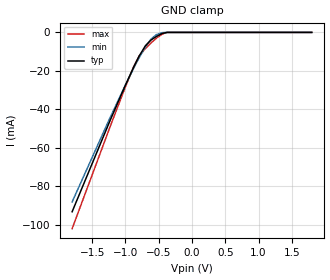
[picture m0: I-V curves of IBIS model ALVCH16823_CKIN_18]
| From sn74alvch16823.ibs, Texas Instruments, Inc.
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[Model]   ALVCH16823_CKIN_18
Model_type  Input
Vinl=0.5775
Vinh=1.2675
| variable   typ   min   max
C_comp   2.88pF   2.16pF   3.34pF
[Temperature Range]   40   100   -40
| Ambient temperature   25   85   -40
[Voltage range]   1.8   1.65   1.95
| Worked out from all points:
|   GND clamp passes 1 mA (typ) near -0.48 V on its own axis
[GND Clamp]
| ALVCH16823_CKIN_18
|   Voltage   I(typ)   I(min)   I(max)
-1.8V     -93.3mA    -88.19mA   -102.1mA
-1.235V   -46.25mA   -44.72mA   -49.56mA
-1V       -27.5mA    -27.4mA    -28.37mA
-875mV    -18.04mA   -18.61mA   -17.75mA
-795mV    -12.45mA   -13.28mA   -12.37mA
-700mV    -6.981mA   -7.539mA   -8.412mA
-615mV    -3.968mA   -3.483mA   -5.497mA
-535mV    -2.13mA    -1.195mA   -3.054mA
-445mV    -515.8uA   -125.4uA   -861.2uA
-375mV    -85.17nA   -8.524uA   -4.38uA
1.8V      24.55pA    142.2pA    23.4pA
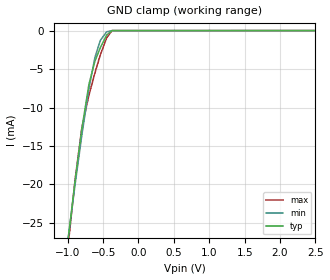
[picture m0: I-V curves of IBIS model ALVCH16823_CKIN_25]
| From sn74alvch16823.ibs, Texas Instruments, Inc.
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[Model]   ALVCH16823_CKIN_25
Model_type  Input
Vinl=0.7
Vinh=1.7
| variable   typ   min   max
C_comp   2.81pF   2.05pF   3.37pF
[Temperature Range]   40   100   -40
| Ambient temperature   25   85   -40
[Voltage range]   2.5   2.3   2.7
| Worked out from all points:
|   GND clamp passes 1 mA (typ) near -0.48 V on its own axis
[GND Clamp]
| ALVCH16823_CKIN_25
|   Voltage   I(typ)   I(min)   I(max)
-2.5V     -153.1mA   -143.6mA   -168.5mA
-1.145V   -38.97mA   -38mA      -41.38mA
-1.11V    -36.17mA   -35.41mA   -38.21mA
-1.08V    -33.78mA   -33.21mA   -35.51mA
-895mV    -19.51mA   -19.99mA   -19.35mA
-800mV    -12.78mA   -13.61mA   -12.64mA
-700mV    -6.981mA   -7.539mA   -8.412mA
-615mV    -3.968mA   -3.483mA   -5.497mA
-540mV    -2.234mA   -1.292mA   -3.196mA
-450mV    -586.7uA   -156.6uA   -959.9uA
-375mV    -85.17nA   -8.524uA   -4.38uA
2.5V      34.28pA    152.6pA    32.5pA
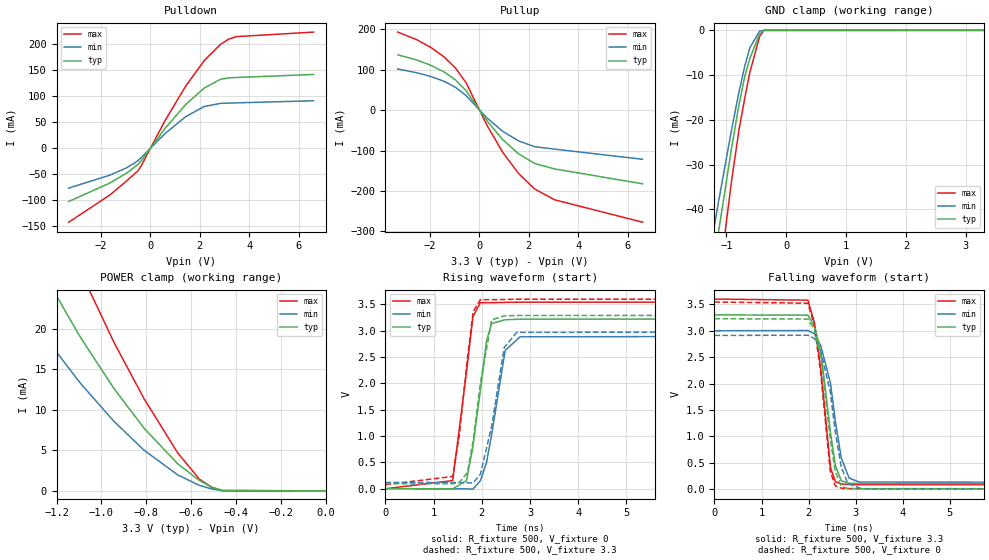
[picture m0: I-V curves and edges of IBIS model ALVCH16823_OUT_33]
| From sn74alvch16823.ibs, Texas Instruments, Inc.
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[Model]   ALVCH16823_OUT_33
Model_type  3-state
Enable   Active-Low
Vref =   0
Rref =   500
Cref =   50p
Vmeas =   1.5
| variable   typ   min   max
C_comp   3.15pF   2.78pF   3.51pF
| C_pullup   4.51pF   3.46pF   5.58pF
| C_pulldown   3.69pF   3.02pF   4.93pF
| C_tri-state   3.15pF   2.78pF   3.51pF
[Temperature Range]   40   100   -40
| Ambient temperature   25   85   -40
[Voltage range]   3.3   3   3.6
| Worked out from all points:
|   slope of the pulldown table from 0 to 0.495 V, typ, clamps not added: 15.7 ohm
|   slope of the pullup table from 0 to 0.495 V, typ, clamps not added: 12 ohm
|   GND clamp passes 1 mA (typ) near -0.45 V on its own axis
|   POWER clamp passes 1 mA (typ) near -0.55 V on its own axis
|   rising waveform, R_fixture 500, V_fixture 0: 20-80 % time 272ps typ, 298ps min, 249ps max; typ from 0 V to 3.23 V
|   falling waveform, R_fixture 500, V_fixture 3.3: 20-80 % time 263ps typ, 302ps min, 236ps max; typ from 3.3 V to 0.098 V
|   rising waveform, R_fixture 500, V_fixture 3.3: 20-80 % time 266ps typ, 295ps min, 249ps max; typ from 0.098 V to 3.3 V
|   falling waveform, R_fixture 500, V_fixture 0: 20-80 % time 260ps typ, 296ps min, 235ps max; typ from 3.23 V to 0 V
[GND Clamp]
| ALVCH16823_OUT_33
|   Voltage   I(typ)   I(min)   I(max)
-3.3V     -252.6mA   -218.9mA   -306mA
-1.38V    -67.44mA   -57.71mA   -83.84mA
-1.33V    -62.86mA   -53.75mA   -78.31mA
-1.235V   -54.25mA   -46.3mA    -67.88mA
-1.12V    -44.01mA   -37.45mA   -55.4mA
-910mV    -26.03mA   -21.97mA   -33.3mA
-790mV    -16.63mA   -13.8mA    -22.27mA
-695mV    -10.4mA    -8.048mA   -15.24mA
-610mV    -6.352mA   -3.965mA   -9.512mA
-445mV    -799.8uA   -166.8uA   -1.357mA
-370mV    -74.7nA    -7.732uA   -89.67nA
3.3V      36.38pA    1.473uA    36pA
[POWER Clamp]
| ALVCH16823_OUT_33
|   Voltage   I(typ)   I(min)   I(max)
-3.3V     160.1mA    121.9mA    218.5mA
-1.45V    36.9mA     26.88mA    51.65mA
-1.265V   27.17mA    19.47mA    38.37mA
-1.105V   19.48mA    13.68mA    27.83mA
-1.085V   18.58mA    13mA       26.58mA
-945mV    12.66mA    8.603mA    18.36mA
-810mV    7.725mA    5.017mA    11.37mA
-660mV    3.343mA    1.976mA    4.686mA
-565mV    1.32mA     697.8uA    1.493mA
-505mV    439.3uA    213.4uA    367.2uA
-460mV    69.26uA    49.23uA    18.1uA
-48.03fV  36.38pA    138pA      39.6pA
[Pulldown]
| ALVCH16823_OUT_33
|   Voltage   I(typ)   I(min)   I(max)
-3.3V     -102.4mA   -76.67mA   -142mA
-1.635V   -66.99mA   -51.95mA   -89.86mA
-965mV    -48.17mA   -38.04mA   -63.16mA
-515mV    -32.04mA   -24.81mA   -44.25mA
-380mV    -25.13mA   -18.81mA   -34.9mA
600mV     37.89mA    27.98mA    53.13mA
1.425V    83.1mA     59.87mA    118.3mA
2.175V    114.7mA    79.5mA     167.1mA
2.835V    131.6mA    85.42mA    198.4mA
3.17V     134.3mA    85.96mA    208.5mA
3.48V     135mA      86.44mA    213.2mA
6.6V      140.8mA    90.43mA    221.9mA
[Pullup]
| ALVCH16823_OUT_33
|   Voltage   I(typ)   I(min)   I(max)
-3.3V     136.7mA    101.6mA    192.9mA
-2.54V    124.1mA    92.55mA    174.4mA
-1.96V    110.8mA    83.11mA    155mA
-1.42V    94.25mA    71.04mA    131.2mA
-970mV    75.07mA    56.69mA    104.3mA
-540mV    48.45mA    36.16mA    68.01mA
315mV     -27.07mA   -19.8mA    -38.27mA
945mV     -72.86mA   -52.43mA   -104.2mA
1.59V     -108.2mA   -76.24mA   -156.9mA
2.235V    -131.9mA   -90.36mA   -194.9mA
3.045V    -145.3mA   -96.39mA   -221.7mA
6.6V      -182.1mA   -121.5mA   -277mA
[Ramp]
| ALVCH16823_OUT_33
| variable   typ   min   max
dV/dt_r   1.94/2.94E-10   1.75/3.07E-10   2.13/2.52E-10
dV/dt_f   1.92/2.65E-10   1.73/3.10E-10   2.12/2.40E-10
R_load = 500
[Rising Waveform]
| ALVCH16823_OUT_33
R_fixture =   500
C_fixture =   0
L_fixture =   0
V_fixture =   0
V_fixture_min = 0
V_fixture_max = 0
|   Time   V(typ)   V(min)   V(max)
0s        50.06pV    2.741nV    38.32pV
1.395ns   -3.019mV   -170.7uV   154.7mV
1.68ns    151.8mV    -2.319mV   2.201V
1.815ns   797.9mV    -8.205mV   3.268V
1.97ns    1.871V     153.5mV    3.531V
2.095ns   2.792V     491.7mV    3.53V
2.2ns     3.134V     1.007V     3.53V
2.485ns   3.208V     2.626V     3.537V
2.795ns   3.218V     2.884V     3.541V
24.99ns   3.228V     2.911V     3.544V
[Falling Waveform]
| ALVCH16823_OUT_33
R_fixture =   500
C_fixture =   0
L_fixture =   0
V_fixture =   3.3
V_fixture_min = 3
V_fixture_max = 3.6
|   Time   V(typ)   V(min)   V(max)
0s        3.3V       3V         3.6V
1.985ns   3.295V     3.004V     3.579V
2.125ns   3.091V     2.942V     3.147V
2.26ns    2.604V     2.713V     2.271V
2.465ns   1.069V     2.006V     408.5mV
2.57ns    439.2mV    1.276V     141.5mV
2.695ns   159.9mV    587.8mV    97.71mV
2.86ns    109.3mV    210.5mV    89.03mV
3.075ns   108.4mV    134.4mV    84.57mV
24.99ns   97.56mV    117.9mV    76.97mV
[Rising Waveform]
| ALVCH16823_OUT_33
R_fixture =   500
C_fixture =   0
L_fixture =   0
V_fixture =   3.3
V_fixture_min = 3
V_fixture_max = 3.6
|   Time   V(typ)   V(min)   V(max)
0s        97.56mV    117.9mV    76.97mV
1.395ns   94.55mV    117.4mV    233.5mV
1.53ns    116mV      116.9mV    993.4mV
1.7ns     306.9mV    114.6mV    2.471V
1.82ns    908mV      109.7mV    3.359V
1.97ns    2.005V     275.3mV    3.589V
2.205ns   3.205V     1.192V     3.587V
2.465ns   3.281V     2.682V     3.593V
2.725ns   3.288V     2.968V     3.597V
24.99ns   3.3V       3V         3.6V
[Falling Waveform]
| ALVCH16823_OUT_33
R_fixture =   500
C_fixture =   0
L_fixture =   0
V_fixture =   0
V_fixture_min = 0
V_fixture_max = 0
|   Time   V(typ)   V(min)   V(max)
0s        3.228V     2.911V     3.544V
1.985ns   3.222V     2.915V     3.521V
2.12ns    3.026V     2.856V     3.107V
2.255ns   2.529V     2.619V     2.22V
2.46ns    954.4mV    1.849V     342mV
2.565ns   337.4mV    1.093V     64.29mV
2.695ns   55.51mV    417.9mV    19.27mV
2.835ns   10.76mV    105.7mV    11.28mV
3.12ns    8.696mV    9.977mV    6.23mV
24.99ns   13.82nV    12.7nV     6.614nV
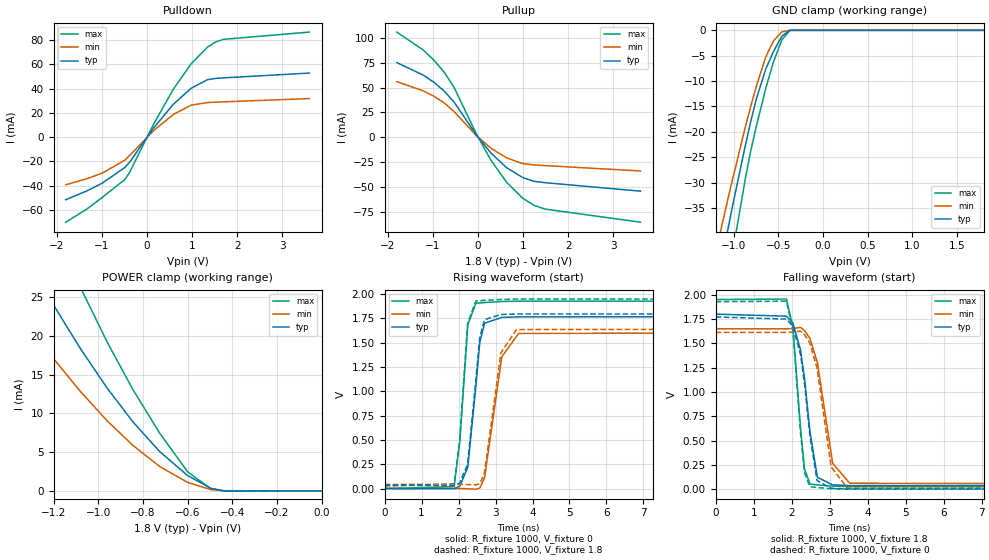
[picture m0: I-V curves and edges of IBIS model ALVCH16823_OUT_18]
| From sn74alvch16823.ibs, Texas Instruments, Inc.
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[Model]   ALVCH16823_OUT_18
Model_type  3-state
Enable   Active-Low
Vref =   0
Rref =   1000
Cref =   30p
Vmeas =   0.9
| variable   typ   min   max
C_comp   3.42pF   3.02pF   3.64pF
| C_pullup   4.78pF   3.56pF   5.56pF
| C_pulldown   4.34pF   3.19pF   5.61pF
| C_tri-state   3.42pF   3.02pF   3.64pF
[Temperature Range]   40   100   -40
| Ambient temperature   25   85   -40
[Voltage range]   1.8   1.65   1.95
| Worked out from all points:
|   slope of the pulldown table from 0 to 0.27 V, typ, clamps not added: 20.1 ohm
|   slope of the pullup table from 0 to 0.27 V, typ, clamps not added: 17.9 ohm
|   GND clamp passes 1 mA (typ) near -0.45 V on its own axis
|   POWER clamp passes 1 mA (typ) near -0.55 V on its own axis
|   rising waveform, R_fixture 1000, V_fixture 0: 20-80 % time 247ps typ, 315ps min, 200ps max; typ from 0 V to 1.77 V
|   falling waveform, R_fixture 1000, V_fixture 1.8: 20-80 % time 311ps typ, 358ps min, 220ps max; typ from 1.8 V to 0.034 V
|   rising waveform, R_fixture 1000, V_fixture 1.8: 20-80 % time 246ps typ, 303ps min, 199ps max; typ from 0.034 V to 1.8 V
|   falling waveform, R_fixture 1000, V_fixture 0: 20-80 % time 315ps typ, 339ps min, 218ps max; typ from 1.77 V to 0 V
[GND Clamp]
| ALVCH16823_OUT_18
|   Voltage   I(typ)   I(min)   I(max)
-1.8V     -106.7mA   -91.79mA   -131.1mA
-1.25V    -55.61mA   -47.47mA   -69.52mA
-1.02V    -35.3mA    -29.94mA   -44.72mA
-870mV    -22.79mA   -19.17mA   -29.34mA
-810mV    -18.11mA   -15.11mA   -23.91mA
-745mV    -13.48mA   -10.96mA   -18.86mA
-640mV    -7.632mA   -5.252mA   -11.45mA
-555mV    -4.229mA   -2.109mA   -6.268mA
-460mV    -1.159mA   -311uA     -1.867mA
-370mV    -74.7nA    -7.732uA   -89.67nA
1.8V      19.88pA    14.61nA    19.65pA
[POWER Clamp]
| ALVCH16823_OUT_18
|   Voltage   I(typ)   I(min)   I(max)
-1.8V     57.24mA    42.5mA     79.26mA
-1.49V    39.11mA    28.57mA    54.66mA
-1.345V   31.27mA    22.59mA    43.98mA
-1.21V    24.44mA    17.41mA    34.63mA
-1.08V    18.36mA    12.83mA    26.27mA
-960mV    13.26mA    9.044mA    19.2mA
-845mV    8.923mA    5.877mA    13.09mA
-725mV    5.082mA    3.156mA    7.457mA
-600mV    1.987mA    1.102mA    2.482mA
-495mV    332.1uA    161uA      252uA
-435mV    1.812uA    32.18uA    111.3pA
-16.28fV  19.88pA    123.2pA    21.45pA
[Pulldown]
| ALVCH16823_OUT_18
|   Voltage   I(typ)   I(min)   I(max)
-1.8V     -51.5mA    -39.24mA   -70mA
-1.335V   -44.31mA   -34.24mA   -59.29mA
-985mV    -37.72mA   -29.46mA   -49.45mA
-485mV    -24.82mA   -18.84mA   -34.69mA
-380mV    -20.38mA   -14.94mA   -28.67mA
150mV     7.659mA    5.483mA    10.94mA
585mV     27.11mA    18.74mA    39.49mA
980mV     40.32mA    26.41mA    60.44mA
1.34V     47.32mA    28.51mA    74.09mA
1.525V    48.45mA    28.83mA    78.49mA
1.7V      48.88mA    29.13mA    80.61mA
3.6V      52.83mA    31.82mA    86.58mA
[Pullup]
| ALVCH16823_OUT_18
|   Voltage   I(typ)   I(min)   I(max)
-1.8V     75.03mA    55.86mA    105.7mA
-1.215V   62.47mA    46.66mA    87.67mA
-970mV    54.97mA    41.02mA    77.14mA
-745mV    46.22mA    34.32mA    65.07mA
-530mV    35.32mA    25.86mA    50.05mA
-40mV     2.478mA    1.761mA    3.559mA
290mV     -16.06mA   -11.19mA   -23.37mA
640mV     -30.82mA   -20.89mA   -45.58mA
990mV     -40.51mA   -26.45mA   -61.24mA
1.235V    -44.28mA   -27.87mA   -68.31mA
1.48V     -45.65mA   -28.47mA   -72.18mA
3.6V      -54.19mA   -33.92mA   -85.39mA
[Ramp]
| ALVCH16823_OUT_18
| variable   typ   min   max
dV/dt_r   1.06/2.57E-10   0.97/3.23E-10   1.16/2.14E-10
dV/dt_f   1.06/3.14E-10   0.97/3.66E-10   1.16/2.30E-10
R_load = 1000
[Rising Waveform]
| ALVCH16823_OUT_18
R_fixture =   1000
C_fixture =   0
L_fixture =   0
V_fixture =   0
V_fixture_min = 0
V_fixture_max = 0
|   Time   V(typ)   V(min)   V(max)
0s        35.68pV    3.585nV    25.8pV
1.88ns    -2.197mV   632.6uV    20.24mV
2.035ns   25.4mV     247uV      487.9mV
2.25ns    219.5mV    -2.364mV   1.685V
2.47ns    1.061V     -6.488mV   1.909V
2.575ns   1.506V     5.977mV    1.91V
2.705ns   1.702V     113.5mV    1.914V
3.17ns    1.761V     1.357V     1.925V
3.625ns   1.767V     1.596V     1.928V
24.99ns   1.771V     1.612V     1.928V
[Falling Waveform]
| ALVCH16823_OUT_18
R_fixture =   1000
C_fixture =   0
L_fixture =   0
V_fixture =   1.8
V_fixture_min = 1.65
V_fixture_max = 1.95
|   Time   V(typ)   V(min)   V(max)
0s        1.8V       1.65V      1.95V
1.86ns    1.779V     1.649V     1.955V
2.03ns    1.708V     1.652V     1.66V
2.23ns    1.432V     1.664V     630.8mV
2.335ns   1.141V     1.631V     208.6mV
2.48ns    588.1mV    1.549V     53.13mV
2.675ns   121.7mV    1.3V       43.26mV
3.075ns   44.13mV    266.9mV    30.69mV
3.525ns   37.06mV    60.81mV    26.56mV
24.99ns   33.84mV    42.82mV    25.9mV
[Rising Waveform]
| ALVCH16823_OUT_18
R_fixture =   1000
C_fixture =   0
L_fixture =   0
V_fixture =   1.8
V_fixture_min = 1.65
V_fixture_max = 1.95
|   Time   V(typ)   V(min)   V(max)
0s        33.84mV    42.82mV    25.9mV
1.88ns    31.64mV    43.03mV    46.74mV
2.03ns    56.94mV    42.69mV    502.1mV
2.245ns   248.2mV    40.73mV    1.7V
2.47ns    1.131V     37.6mV     1.932V
2.575ns   1.558V     51.21mV    1.933V
2.7ns     1.737V     157.5mV    1.937V
3.145ns   1.791V     1.396V     1.946V
3.565ns   1.796V     1.636V     1.95V
24.99ns   1.8V       1.65V      1.95V
[Falling Waveform]
| ALVCH16823_OUT_18
R_fixture =   1000
C_fixture =   0
L_fixture =   0
V_fixture =   0
V_fixture_min = 0
V_fixture_max = 0
|   Time   V(typ)   V(min)   V(max)
0s        1.771V     1.612V     1.928V
1.86ns    1.749V     1.612V     1.933V
2.03ns    1.674V     1.615V     1.631V
2.23ns    1.383V     1.625V     581.8mV
2.335ns   1.088V     1.589V     172.2mV
2.475ns   553.3mV    1.504V     24.9mV
2.665ns   88.43mV    1.246V     16.69mV
3.035ns   8.507mV    228mV      5.104mV
3.46ns    3.251mV    12.86mV    893.6uV
24.99ns   12.81nV    8.08nV     6.311nV
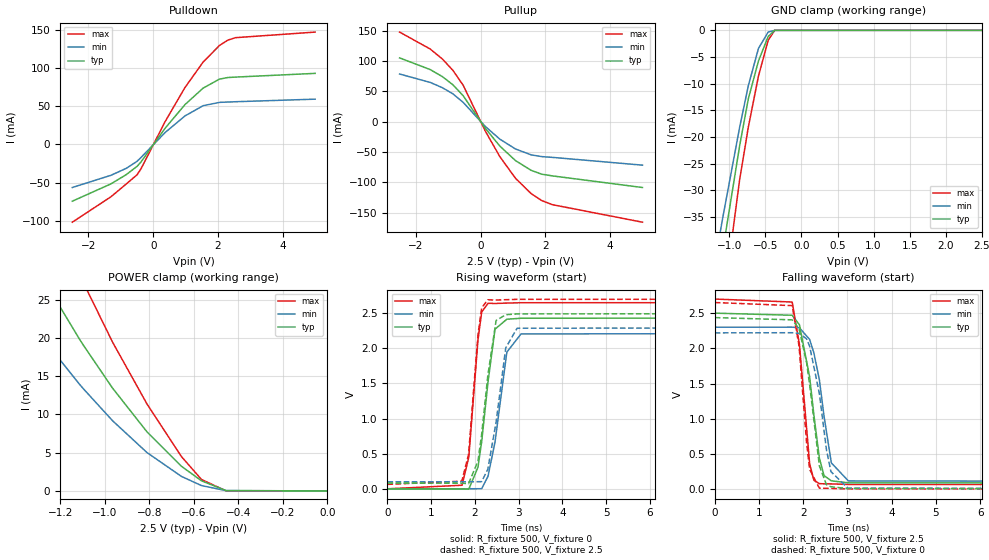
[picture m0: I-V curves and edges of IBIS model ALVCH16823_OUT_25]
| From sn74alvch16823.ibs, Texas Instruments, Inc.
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[Model]   ALVCH16823_OUT_25
Model_type  3-state
Enable   Active-Low
Vref =   0
Rref =   500
Cref =   30p
Vmeas =   1.25
| variable   typ   min   max
C_comp   3.28pF   2.88pF   3.56pF
| C_pullup   4.49pF   2.69pF   5.52pF
| C_pulldown   3.95pF   3.12pF   5.06pF
| C_tri-state   3.28pF   2.88pF   3.56pF
[Temperature Range]   40   100   -40
| Ambient temperature   25   85   -40
[Voltage range]   2.5   2.3   2.7
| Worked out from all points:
|   slope of the pulldown table from 0 to 0.375 V, typ, clamps not added: 17.3 ohm
|   slope of the pullup table from 0 to 0.375 V, typ, clamps not added: 14 ohm
|   GND clamp passes 1 mA (typ) near -0.45 V on its own axis
|   POWER clamp passes 1 mA (typ) near -0.55 V on its own axis
|   rising waveform, R_fixture 500, V_fixture 0: 20-80 % time 252ps typ, 276ps min, 197ps max; typ from 0 V to 2.44 V
|   falling waveform, R_fixture 500, V_fixture 2.5: 20-80 % time 290ps typ, 307ps min, 209ps max; typ from 2.5 V to 0.081 V
|   rising waveform, R_fixture 500, V_fixture 2.5: 20-80 % time 249ps typ, 269ps min, 196ps max; typ from 0.081 V to 2.5 V
|   falling waveform, R_fixture 500, V_fixture 0: 20-80 % time 289ps typ, 302ps min, 207ps max; typ from 2.44 V to 0 V
[GND Clamp]
| ALVCH16823_OUT_25
|   Voltage   I(typ)   I(min)   I(max)
-2.5V     -174.1mA   -150.4mA   -211.9mA
-1.35V    -64.69mA   -55.33mA   -80.52mA
-1.31V    -61.04mA   -52.17mA   -76.1mA
-1.23V    -53.81mA   -45.91mA   -67.33mA
-1.12V    -44.01mA   -37.45mA   -55.4mA
-1.085V   -40.93mA   -34.8mA    -51.64mA
-855mV    -21.59mA   -18.14mA   -27.92mA
-735mV    -12.82mA   -10.36mA   -18.12mA
-595mV    -5.75mA    -3.392mA   -8.586mA
-460mV    -1.159mA   -311uA     -1.867mA
-370mV    -74.7nA    -7.732uA   -89.67nA
2.5V      27.58pA    69.12nA    27.3pA
[POWER Clamp]
| ALVCH16823_OUT_25
|   Voltage   I(typ)   I(min)   I(max)
-2.5V     102.8mA    77.76mA    140.9mA
-1.49V    39.11mA    28.57mA    54.66mA
-1.465V   37.73mA    27.52mA    52.78mA
-1.275V   27.67mA    19.85mA    39.06mA
-1.115V   19.94mA    14.02mA    28.46mA
-1.095V   19.03mA    13.34mA    27.2mA
-965mV    13.46mA    9.193mA    19.48mA
-810mV    7.725mA    5.017mA    11.37mA
-655mV    3.221mA    1.895mA    4.483mA
-565mV    1.32mA     697.8uA    1.493mA
-455mV    47.34uA    43.04uA    6.654uA
-31.15fV  27.58pA    130.3pA    29.7pA
[Pulldown]
| ALVCH16823_OUT_25
|   Voltage   I(typ)   I(min)   I(max)
-2.5V     -74.23mA   -56.33mA   -101.7mA
-1.31V    -51.68mA   -40.42mA   -68.57mA
-835mV    -39.54mA   -31.32mA   -51.76mA
-500mV    -28.68mA   -22.1mA    -39.7mA
-380mV    -23.03mA   -17.16mA   -32.06mA
365mV     21.12mA    15.5mA     29.72mA
980mV     52.08mA    37.26mA    74.44mA
1.54V     73.64mA    50.63mA    107.7mA
2.045V    85.4mA     54.98mA    129.4mA
2.3V      87.46mA    55.42mA    136.3mA
2.54V     88.04mA    55.82mA    139.6mA
5V        92.91mA    59.19mA    146.9mA
[Pullup]
| ALVCH16823_OUT_25
|   Voltage   I(typ)   I(min)   I(max)
-2.5V     104.9mA    78.37mA    147.4mA
-1.555V   85.67mA    64.51mA    119.5mA
-1.18V    74.08mA    55.9mA     103.1mA
-855mV    60.68mA    45.73mA    84.46mA
-535mV    42.47mA    31.58mA    59.7mA
140mV     -10.56mA   -7.678mA   -14.97mA
595mV     -40.3mA    -28.86mA   -57.72mA
1.08V     -64.27mA   -45.09mA   -93.34mA
1.565V    -80.3mA    -54.78mA   -118.7mA
1.89V     -86.6mA    -57.62mA   -130mA
2.215V    -89.34mA   -58.86mA   -136.7mA
5V        -108.5mA   -71.69mA   -165.6mA
[Ramp]
| ALVCH16823_OUT_25
| variable   typ   min   max
dV/dt_r   1.47/2.63E-10   1.33/2.92E-10   1.59/2.08E-10
dV/dt_f   1.45/3.05E-10   1.32/3.16E-10   1.58/2.18E-10
R_load = 500
[Rising Waveform]
| ALVCH16823_OUT_25
R_fixture =   500
C_fixture =   0
L_fixture =   0
V_fixture =   0
V_fixture_min = 0
V_fixture_max = 0
|   Time   V(typ)   V(min)   V(max)
0s        41.89pV    3.001nV    31.31pV
1.705ns   -1.257mV   341.9uV    50.51mV
1.86ns    -5.134mV   472.9uV    448.7mV
2.07ns    306.2mV    1.21mV     2.117V
2.155ns   672.8mV    1.593mV    2.515V
2.3ns     1.522V     179.1mV    2.64V
2.46ns    2.272V     666.2mV    2.637V
2.73ns    2.413V     1.945V     2.643V
3.055ns   2.427V     2.204V     2.648V
24.99ns   2.437V     2.22V      2.651V
[Falling Waveform]
| ALVCH16823_OUT_25
R_fixture =   500
C_fixture =   0
L_fixture =   0
V_fixture =   2.5
V_fixture_min = 2.3
V_fixture_max = 2.7
|   Time   V(typ)   V(min)   V(max)
0s        2.5V       2.3V       2.7V
1.75ns    2.47V      2.301V     2.658V
1.915ns   2.333V     2.291V     2.05V
2.145ns   1.593V     2.126V     361mV
2.24ns    1.058V     1.936V     125.7mV
2.365ns   440mV      1.552V     78.44mV
2.47ns    192.9mV    1.038V     75.98mV
2.635ns   118.2mV    373.5mV    74.67mV
3.02ns    90.29mV    117mV      67.11mV
24.99ns   80.95mV    99.73mV    62.96mV
[Rising Waveform]
| ALVCH16823_OUT_25
R_fixture =   500
C_fixture =   0
L_fixture =   0
V_fixture =   2.5
V_fixture_min = 2.3
V_fixture_max = 2.7
|   Time   V(typ)   V(min)   V(max)
0s        80.94mV    99.73mV    62.96mV
1.7ns     79.51mV    99.55mV    108.5mV
1.855ns   74.41mV    99.44mV    491.8mV
2.07ns    393.6mV    101.2mV    2.193V
2.155ns   780.1mV    102.2mV    2.576V
2.295ns   1.612V     276.9mV    2.69V
2.485ns   2.396V     950mV      2.686V
2.705ns   2.477V     2.006V     2.691V
2.965ns   2.489V     2.285V     2.696V
24.99ns   2.5V       2.3V       2.7V
[Falling Waveform]
| ALVCH16823_OUT_25
R_fixture =   500
C_fixture =   0
L_fixture =   0
V_fixture =   0
V_fixture_min = 0
V_fixture_max = 0
|   Time   V(typ)   V(min)   V(max)
0s        2.437V     2.22V      2.651V
1.75ns    2.405V     2.222V     2.607V
1.905ns   2.28V      2.213V     2.034V
2.075ns   1.802V     2.135V     667.1mV
2.145ns   1.482V     2.03V      279.7mV
2.365ns   330.6mV    1.357V     13.75mV
2.525ns   62.45mV    560.6mV    11.92mV
2.625ns   34.54mV    250.1mV    10.8mV
3.01ns    8.232mV    14.83mV    3.861mV
24.99ns   16.79nV    20.35nV    10.81nV
